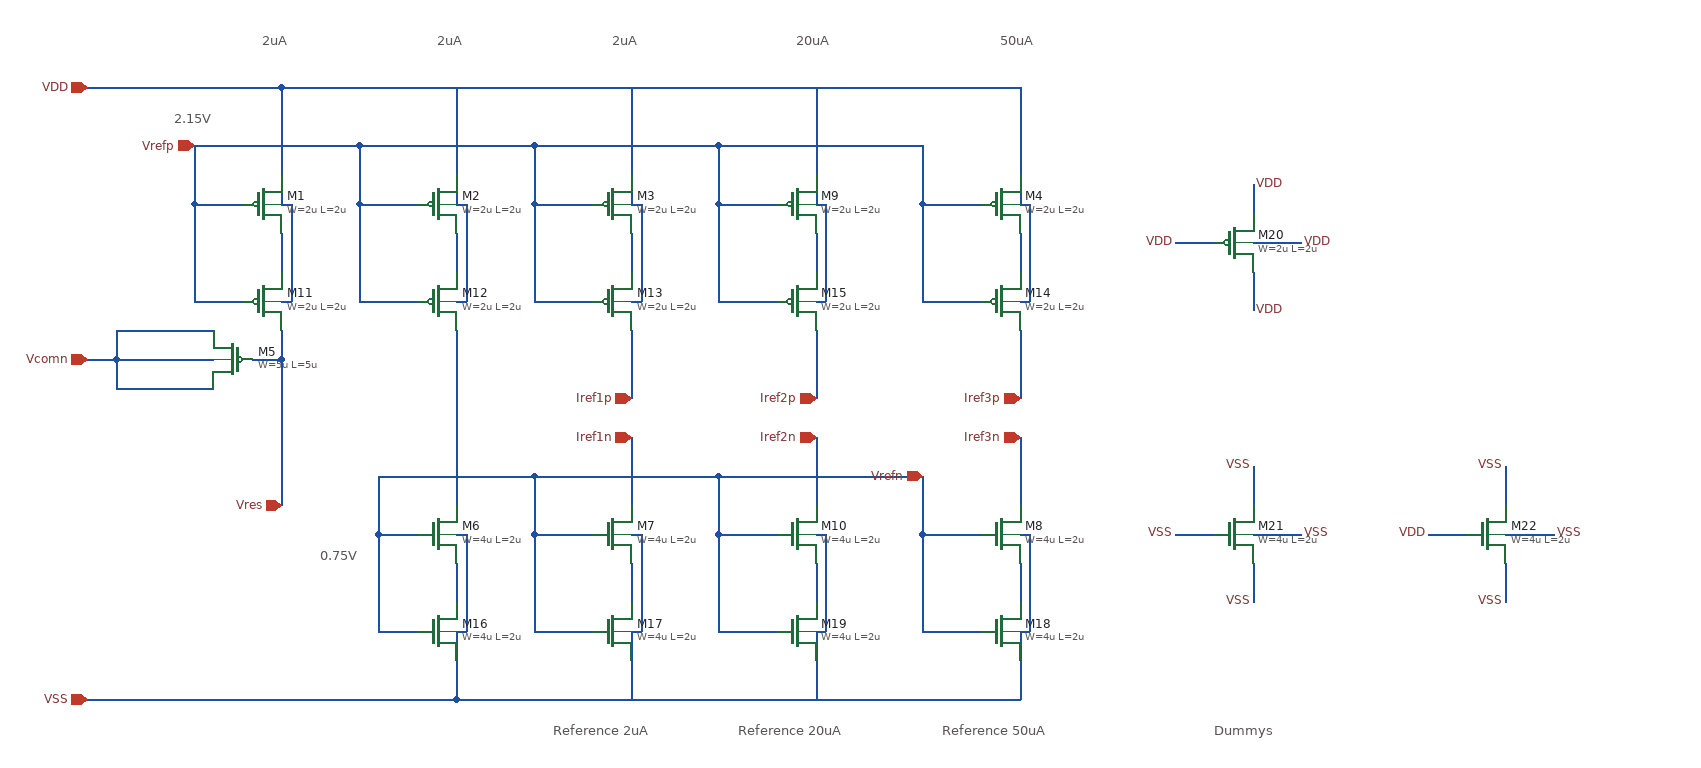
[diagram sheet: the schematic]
v {xschem version=3.4.7 file_version=1.2}
G {}
K {}
V {}
S {}
E {}
T {Reference 2uA} 630 -60 0 0 0.4 0.4 {}
T {Reference 50uA} 1030 -60 0 0 0.4 0.4 {}
T {2.15V} 240 -690 0 0 0.4 0.4 {}
T {0.75V} 390 -240 0 0 0.4 0.4 {}
T {Reference 20uA} 820 -60 0 0 0.4 0.4 {}
T {2uA} 330 -770 0 0 0.4 0.4 {}
T {2uA} 510 -770 0 0 0.4 0.4 {}
T {2uA} 690 -770 0 0 0.4 0.4 {}
T {20uA} 880 -770 0 0 0.4 0.4 {}
T {50uA} 1090 -770 0 0 0.4 0.4 {}
T {Dummys} 1310 -60 0 0 0.4 0.4 {}
N 350 -430 350 -280 {
lab=Vres}
N 350 -710 350 -590 {
lab=VDD}
N 530 -710 530 -590 {
lab=VDD}
N 430 -590 490 -590 {
lab=Vrefp}
N 260 -650 260 -590 {
lab=Vrefp}
N 430 -650 430 -590 {
lab=Vrefp}
N 530 -330 530 -280 {
lab=Vrefn}
N 450 -250 490 -250 {
lab=Vrefn}
N 610 -250 670 -250 {
lab=Vrefn}
N 610 -310 610 -250 {
lab=Vrefn}
N 610 -590 670 -590 {
lab=Vrefp}
N 610 -650 610 -590 {
lab=Vrefp}
N 710 -710 710 -590 {
lab=VDD}
N 710 -350 710 -280 {
lab=Iref2n}
N 710 -460 710 -390 {
lab=Iref1p}
N 1010 -250 1070 -250 {
lab=Vrefn}
N 1010 -310 1010 -250 {
lab=Vrefn}
N 1010 -590 1070 -590 {
lab=Vrefp}
N 1010 -650 1010 -590 {
lab=Vrefp}
N 1110 -710 1110 -590 {
lab=VDD}
N 1110 -350 1110 -280 {
lab=Iref3n}
N 1110 -460 1110 -390 {
lab=Iref3p}
N 180 -430 280 -430 {
lab=Vcomn}
N 180 -400 280 -400 {
lab=Vcomn}
N 320 -430 350 -430 {
lab=Vres}
N 180 -430 180 -400 {
lab=Vcomn}
N 180 -460 280 -460 {
lab=Vcomn}
N 150 -430 180 -430 {
lab=Vcomn}
N 260 -590 310 -590 {lab=Vrefp}
N 530 -460 530 -330 {
lab=Vrefn}
N 180 -460 180 -430 {
lab=Vcomn}
N 350 -460 350 -430 {
lab=Vres}
N 800 -250 860 -250 {
lab=Vrefn}
N 800 -310 800 -250 {
lab=Vrefn}
N 800 -590 860 -590 {
lab=Vrefp}
N 800 -650 800 -590 {
lab=Vrefp}
N 900 -710 900 -590 {
lab=VDD}
N 900 -350 900 -280 {
lab=Iref2n}
N 900 -460 900 -390 {
lab=Iref2p}
N 350 -560 350 -520 {lab=#net1}
N 530 -560 530 -520 {lab=#net2}
N 710 -560 710 -520 {lab=#net3}
N 900 -560 900 -520 {lab=#net4}
N 1110 -560 1110 -520 {lab=#net5}
N 1110 -150 1110 -80 {lab=VSS}
N 530 -490 540 -490 {lab=VDD}
N 540 -590 540 -490 {lab=VDD}
N 530 -590 540 -590 {lab=VDD}
N 710 -590 720 -590 {lab=VDD}
N 720 -590 720 -490 {lab=VDD}
N 710 -490 720 -490 {lab=VDD}
N 900 -590 910 -590 {lab=VDD}
N 910 -590 910 -490 {lab=VDD}
N 900 -490 910 -490 {lab=VDD}
N 1110 -590 1120 -590 {lab=VDD}
N 1120 -590 1120 -490 {lab=VDD}
N 1110 -490 1120 -490 {lab=VDD}
N 1110 -220 1110 -180 {lab=#net6}
N 1110 -250 1120 -250 {lab=VSS}
N 1120 -250 1120 -150 {lab=VSS}
N 1110 -150 1120 -150 {lab=VSS}
N 900 -220 900 -180 {lab=#net7}
N 900 -250 910 -250 {lab=VSS}
N 910 -250 910 -150 {lab=VSS}
N 900 -150 910 -150 {lab=VSS}
N 710 -250 720 -250 {lab=VSS}
N 720 -250 720 -150 {lab=VSS}
N 710 -150 720 -150 {lab=VSS}
N 710 -220 710 -180 {lab=#net8}
N 530 -220 530 -180 {lab=#net9}
N 530 -250 540 -250 {lab=VSS}
N 540 -250 540 -150 {lab=VSS}
N 530 -150 540 -150 {lab=VSS}
N 430 -490 490 -490 {lab=Vrefp}
N 430 -590 430 -490 {lab=Vrefp}
N 610 -490 670 -490 {lab=Vrefp}
N 610 -590 610 -490 {lab=Vrefp}
N 800 -490 860 -490 {lab=Vrefp}
N 800 -590 800 -490 {lab=Vrefp}
N 1010 -490 1070 -490 {lab=Vrefp}
N 1010 -590 1010 -490 {lab=Vrefp}
N 1010 -250 1010 -150 {lab=Vrefn}
N 1010 -150 1070 -150 {lab=Vrefn}
N 800 -250 800 -150 {lab=Vrefn}
N 800 -150 860 -150 {lab=Vrefn}
N 610 -250 610 -150 {lab=Vrefn}
N 610 -150 670 -150 {lab=Vrefn}
N 450 -250 450 -150 {lab=Vrefn}
N 450 -150 490 -150 {lab=Vrefn}
N 530 -150 530 -80 {lab=VSS}
N 710 -150 710 -80 {lab=VSS}
N 900 -150 900 -80 {lab=VSS}
N 260 -490 310 -490 {lab=Vrefp}
N 260 -590 260 -490 {lab=Vrefp}
N 350 -490 360 -490 {lab=VDD}
N 360 -590 360 -490 {lab=VDD}
N 350 -590 360 -590 {lab=VDD}
N 530 -80 1110 -80 {lab=VSS}
N 800 -310 1010 -310 {lab=Vrefn}
N 610 -310 800 -310 {lab=Vrefn}
N 450 -310 450 -250 {lab=Vrefn}
N 800 -650 1010 -650 {lab=Vrefp}
N 610 -650 800 -650 {lab=Vrefp}
N 430 -650 610 -650 {lab=Vrefp}
N 350 -710 1110 -710 {lab=VDD}
N 150 -710 350 -710 {lab=VDD}
N 150 -80 530 -80 {lab=VSS}
N 450 -310 530 -310 {lab=Vrefn}
N 530 -310 610 -310 {lab=Vrefn}
N 260 -650 430 -650 {lab=Vrefp}
N 1350 -610 1350 -590 {lab=VDD}
N 1350 -590 1350 -580 {lab=VDD}
N 1270 -550 1310 -550 {lab=VDD}
N 1350 -550 1400 -550 {lab=VDD}
N 1350 -520 1350 -480 {lab=VDD}
N 1350 -320 1350 -280 {lab=VSS}
N 1350 -250 1400 -250 {lab=VSS}
N 1270 -250 1310 -250 {lab=VSS}
N 1350 -220 1350 -180 {lab=VSS}
N 1610 -320 1610 -280 {lab=VSS}
N 1610 -250 1660 -250 {lab=VSS}
N 1530 -250 1570 -250 {lab=VDD}
N 1610 -220 1610 -180 {lab=VSS}
C {iopin.sym} 150 -710 2 0 {name=p23 lab=VDD}
C {iopin.sym} 150 -80 2 0 {name=p24 lab=VSS}
C {iopin.sym} 260 -650 2 0 {name=p25 lab=Vrefp}
C {iopin.sym} 1010 -310 0 0 {name=p27 lab=Vrefn}
C {iopin.sym} 710 -350 0 0 {name=p15 lab=Iref1n}
C {iopin.sym} 1110 -350 0 0 {name=p21 lab=Iref3n}
C {iopin.sym} 710 -390 0 0 {name=p26 lab=Iref1p}
C {iopin.sym} 1110 -390 0 0 {name=p28 lab=Iref3p}
C {iopin.sym} 350 -280 2 0 {name=p29 lab=Vres}
C {iopin.sym} 150 -430 2 0 {name=p2 lab=Vcomn}
C {symbols/nfet_03v3.sym} 510 -250 0 0 {name=M6
L=2u
W=4u
nf=1
m=2
ad="'int((nf+1)/2) * W/nf * 0.18u'"
pd="'2*int((nf+1)/2) * (W/nf + 0.18u)'"
as="'int((nf+2)/2) * W/nf * 0.18u'"
ps="'2*int((nf+2)/2) * (W/nf + 0.18u)'"
nrd="'0.18u / W'" nrs="'0.18u / W'"
sa=0 sb=0 sd=0
model=nfet_03v3
spiceprefix=X
}
C {symbols/pfet_03v3.sym} 300 -430 0 1 {name=M5
L=5u
W=5u
nf=1
m=60
ad="'int((nf+1)/2) * W/nf * 0.18u'"
pd="'2*int((nf+1)/2) * (W/nf + 0.18u)'"
as="'int((nf+2)/2) * W/nf * 0.18u'"
ps="'2*int((nf+2)/2) * (W/nf + 0.18u)'"
nrd="'0.18u / W'" nrs="'0.18u / W'"
sa=0 sb=0 sd=0
model=pfet_03v3
spiceprefix=X
}
C {symbols/pfet_03v3.sym} 330 -590 0 0 {name=M1
L=2u
W=2u
nf=1
m=2
ad="'int((nf+1)/2) * W/nf * 0.18u'"
pd="'2*int((nf+1)/2) * (W/nf + 0.18u)'"
as="'int((nf+2)/2) * W/nf * 0.18u'"
ps="'2*int((nf+2)/2) * (W/nf + 0.18u)'"
nrd="'0.18u / W'" nrs="'0.18u / W'"
sa=0 sb=0 sd=0
model=pfet_03v3
spiceprefix=X
}
C {symbols/pfet_03v3.sym} 510 -590 0 0 {name=M2
L=2u
W=2u
nf=1
m=2
ad="'int((nf+1)/2) * W/nf * 0.18u'"
pd="'2*int((nf+1)/2) * (W/nf + 0.18u)'"
as="'int((nf+2)/2) * W/nf * 0.18u'"
ps="'2*int((nf+2)/2) * (W/nf + 0.18u)'"
nrd="'0.18u / W'" nrs="'0.18u / W'"
sa=0 sb=0 sd=0
model=pfet_03v3
spiceprefix=X
}
C {symbols/pfet_03v3.sym} 690 -590 0 0 {name=M3
L=2u
W=2u
nf=1
m=2
ad="'int((nf+1)/2) * W/nf * 0.18u'"
pd="'2*int((nf+1)/2) * (W/nf + 0.18u)'"
as="'int((nf+2)/2) * W/nf * 0.18u'"
ps="'2*int((nf+2)/2) * (W/nf + 0.18u)'"
nrd="'0.18u / W'" nrs="'0.18u / W'"
sa=0 sb=0 sd=0
model=pfet_03v3
spiceprefix=X
}
C {symbols/pfet_03v3.sym} 1090 -590 0 0 {name=M4
L=2u
W=2u
nf=1
m=50
ad="'int((nf+1)/2) * W/nf * 0.18u'"
pd="'2*int((nf+1)/2) * (W/nf + 0.18u)'"
as="'int((nf+2)/2) * W/nf * 0.18u'"
ps="'2*int((nf+2)/2) * (W/nf + 0.18u)'"
nrd="'0.18u / W'" nrs="'0.18u / W'"
sa=0 sb=0 sd=0
model=pfet_03v3
spiceprefix=X
}
C {symbols/nfet_03v3.sym} 690 -250 0 0 {name=M7
L=2u
W=4u
nf=1
m=2
ad="'int((nf+1)/2) * W/nf * 0.18u'"
pd="'2*int((nf+1)/2) * (W/nf + 0.18u)'"
as="'int((nf+2)/2) * W/nf * 0.18u'"
ps="'2*int((nf+2)/2) * (W/nf + 0.18u)'"
nrd="'0.18u / W'" nrs="'0.18u / W'"
sa=0 sb=0 sd=0
model=nfet_03v3
spiceprefix=X
}
C {symbols/nfet_03v3.sym} 1090 -250 0 0 {name=M8
L=2u
W=4u
nf=1
m=50
ad="'int((nf+1)/2) * W/nf * 0.18u'"
pd="'2*int((nf+1)/2) * (W/nf + 0.18u)'"
as="'int((nf+2)/2) * W/nf * 0.18u'"
ps="'2*int((nf+2)/2) * (W/nf + 0.18u)'"
nrd="'0.18u / W'" nrs="'0.18u / W'"
sa=0 sb=0 sd=0
model=nfet_03v3
spiceprefix=X
}
C {symbols/pfet_03v3.sym} 880 -590 0 0 {name=M9
L=2u
W=2u
nf=1
m=20
ad="'int((nf+1)/2) * W/nf * 0.18u'"
pd="'2*int((nf+1)/2) * (W/nf + 0.18u)'"
as="'int((nf+2)/2) * W/nf * 0.18u'"
ps="'2*int((nf+2)/2) * (W/nf + 0.18u)'"
nrd="'0.18u / W'" nrs="'0.18u / W'"
sa=0 sb=0 sd=0
model=pfet_03v3
spiceprefix=X
}
C {symbols/nfet_03v3.sym} 880 -250 0 0 {name=M10
L=2u
W=4u
nf=1
m=20
ad="'int((nf+1)/2) * W/nf * 0.18u'"
pd="'2*int((nf+1)/2) * (W/nf + 0.18u)'"
as="'int((nf+2)/2) * W/nf * 0.18u'"
ps="'2*int((nf+2)/2) * (W/nf + 0.18u)'"
nrd="'0.18u / W'" nrs="'0.18u / W'"
sa=0 sb=0 sd=0
model=nfet_03v3
spiceprefix=X
}
C {iopin.sym} 900 -390 0 0 {name=p35 lab=Iref2p}
C {iopin.sym} 900 -350 0 0 {name=p36 lab=Iref2n}
C {symbols/pfet_03v3.sym} 330 -490 0 0 {name=M11
L=2u
W=2u
nf=1
m=2
ad="'int((nf+1)/2) * W/nf * 0.18u'"
pd="'2*int((nf+1)/2) * (W/nf + 0.18u)'"
as="'int((nf+2)/2) * W/nf * 0.18u'"
ps="'2*int((nf+2)/2) * (W/nf + 0.18u)'"
nrd="'0.18u / W'" nrs="'0.18u / W'"
sa=0 sb=0 sd=0
model=pfet_03v3
spiceprefix=X
}
C {symbols/pfet_03v3.sym} 510 -490 0 0 {name=M12
L=2u
W=2u
nf=1
m=2
ad="'int((nf+1)/2) * W/nf * 0.18u'"
pd="'2*int((nf+1)/2) * (W/nf + 0.18u)'"
as="'int((nf+2)/2) * W/nf * 0.18u'"
ps="'2*int((nf+2)/2) * (W/nf + 0.18u)'"
nrd="'0.18u / W'" nrs="'0.18u / W'"
sa=0 sb=0 sd=0
model=pfet_03v3
spiceprefix=X
}
C {symbols/pfet_03v3.sym} 690 -490 0 0 {name=M13
L=2u
W=2u
nf=1
m=2
ad="'int((nf+1)/2) * W/nf * 0.18u'"
pd="'2*int((nf+1)/2) * (W/nf + 0.18u)'"
as="'int((nf+2)/2) * W/nf * 0.18u'"
ps="'2*int((nf+2)/2) * (W/nf + 0.18u)'"
nrd="'0.18u / W'" nrs="'0.18u / W'"
sa=0 sb=0 sd=0
model=pfet_03v3
spiceprefix=X
}
C {symbols/pfet_03v3.sym} 1090 -490 0 0 {name=M14
L=2u
W=2u
nf=1
m=50
ad="'int((nf+1)/2) * W/nf * 0.18u'"
pd="'2*int((nf+1)/2) * (W/nf + 0.18u)'"
as="'int((nf+2)/2) * W/nf * 0.18u'"
ps="'2*int((nf+2)/2) * (W/nf + 0.18u)'"
nrd="'0.18u / W'" nrs="'0.18u / W'"
sa=0 sb=0 sd=0
model=pfet_03v3
spiceprefix=X
}
C {symbols/pfet_03v3.sym} 880 -490 0 0 {name=M15
L=2u
W=2u
nf=1
m=20
ad="'int((nf+1)/2) * W/nf * 0.18u'"
pd="'2*int((nf+1)/2) * (W/nf + 0.18u)'"
as="'int((nf+2)/2) * W/nf * 0.18u'"
ps="'2*int((nf+2)/2) * (W/nf + 0.18u)'"
nrd="'0.18u / W'" nrs="'0.18u / W'"
sa=0 sb=0 sd=0
model=pfet_03v3
spiceprefix=X
}
C {symbols/nfet_03v3.sym} 510 -150 0 0 {name=M16
L=2u
W=4u
nf=1
m=2
ad="'int((nf+1)/2) * W/nf * 0.18u'"
pd="'2*int((nf+1)/2) * (W/nf + 0.18u)'"
as="'int((nf+2)/2) * W/nf * 0.18u'"
ps="'2*int((nf+2)/2) * (W/nf + 0.18u)'"
nrd="'0.18u / W'" nrs="'0.18u / W'"
sa=0 sb=0 sd=0
model=nfet_03v3
spiceprefix=X
}
C {symbols/nfet_03v3.sym} 690 -150 0 0 {name=M17
L=2u
W=4u
nf=1
m=2
ad="'int((nf+1)/2) * W/nf * 0.18u'"
pd="'2*int((nf+1)/2) * (W/nf + 0.18u)'"
as="'int((nf+2)/2) * W/nf * 0.18u'"
ps="'2*int((nf+2)/2) * (W/nf + 0.18u)'"
nrd="'0.18u / W'" nrs="'0.18u / W'"
sa=0 sb=0 sd=0
model=nfet_03v3
spiceprefix=X
}
C {symbols/nfet_03v3.sym} 1090 -150 0 0 {name=M18
L=2u
W=4u
nf=1
m=50
ad="'int((nf+1)/2) * W/nf * 0.18u'"
pd="'2*int((nf+1)/2) * (W/nf + 0.18u)'"
as="'int((nf+2)/2) * W/nf * 0.18u'"
ps="'2*int((nf+2)/2) * (W/nf + 0.18u)'"
nrd="'0.18u / W'" nrs="'0.18u / W'"
sa=0 sb=0 sd=0
model=nfet_03v3
spiceprefix=X
}
C {symbols/nfet_03v3.sym} 880 -150 0 0 {name=M19
L=2u
W=4u
nf=1
m=20
ad="'int((nf+1)/2) * W/nf * 0.18u'"
pd="'2*int((nf+1)/2) * (W/nf + 0.18u)'"
as="'int((nf+2)/2) * W/nf * 0.18u'"
ps="'2*int((nf+2)/2) * (W/nf + 0.18u)'"
nrd="'0.18u / W'" nrs="'0.18u / W'"
sa=0 sb=0 sd=0
model=nfet_03v3
spiceprefix=X
}
C {symbols/pfet_03v3.sym} 1330 -550 0 0 {name=M20
L=2u
W=2u
nf=1
m=192
ad="'int((nf+1)/2) * W/nf * 0.18u'"
pd="'2*int((nf+1)/2) * (W/nf + 0.18u)'"
as="'int((nf+2)/2) * W/nf * 0.18u'"
ps="'2*int((nf+2)/2) * (W/nf + 0.18u)'"
nrd="'0.18u / W'" nrs="'0.18u / W'"
sa=0 sb=0 sd=0
model=pfet_03v3
spiceprefix=X
}
C {lab_pin.sym} 1350 -610 0 1 {name=p11 sig_type=std_logic lab=VDD}
C {lab_pin.sym} 1400 -550 0 1 {name=p1 sig_type=std_logic lab=VDD}
C {lab_pin.sym} 1350 -480 0 1 {name=p3 sig_type=std_logic lab=VDD}
C {lab_pin.sym} 1270 -550 0 0 {name=p4 sig_type=std_logic lab=VDD}
C {symbols/nfet_03v3.sym} 1330 -250 0 0 {name=M21
L=2u
W=4u
nf=1
m=180
ad="'int((nf+1)/2) * W/nf * 0.18u'"
pd="'2*int((nf+1)/2) * (W/nf + 0.18u)'"
as="'int((nf+2)/2) * W/nf * 0.18u'"
ps="'2*int((nf+2)/2) * (W/nf + 0.18u)'"
nrd="'0.18u / W'" nrs="'0.18u / W'"
sa=0 sb=0 sd=0
model=nfet_03v3
spiceprefix=X
}
C {lab_pin.sym} 1350 -320 0 0 {name=p5 sig_type=std_logic lab=VSS}
C {lab_pin.sym} 1270 -250 0 0 {name=p6 sig_type=std_logic lab=VSS}
C {lab_pin.sym} 1350 -180 0 0 {name=p7 sig_type=std_logic lab=VSS}
C {lab_pin.sym} 1400 -250 0 1 {name=p8 sig_type=std_logic lab=VSS}
C {symbols/nfet_03v3.sym} 1590 -250 0 0 {name=M22
L=2u
W=4u
nf=1
m=16
ad="'int((nf+1)/2) * W/nf * 0.18u'"
pd="'2*int((nf+1)/2) * (W/nf + 0.18u)'"
as="'int((nf+2)/2) * W/nf * 0.18u'"
ps="'2*int((nf+2)/2) * (W/nf + 0.18u)'"
nrd="'0.18u / W'" nrs="'0.18u / W'"
sa=0 sb=0 sd=0
model=nfet_03v3
spiceprefix=X
}
C {lab_pin.sym} 1610 -320 0 0 {name=p9 sig_type=std_logic lab=VSS}
C {lab_pin.sym} 1530 -250 0 0 {name=p10 sig_type=std_logic lab=VDD}
C {lab_pin.sym} 1610 -180 0 0 {name=p12 sig_type=std_logic lab=VSS}
C {lab_pin.sym} 1660 -250 0 1 {name=p13 sig_type=std_logic lab=VSS}
